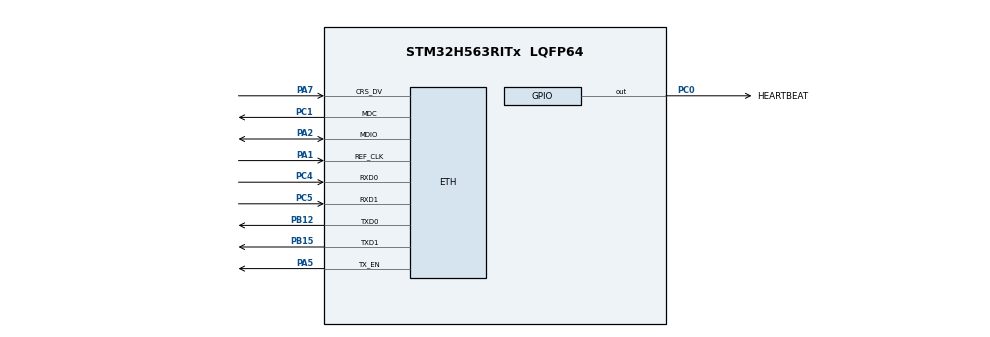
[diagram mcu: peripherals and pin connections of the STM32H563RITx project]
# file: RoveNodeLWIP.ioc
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CORTEX_M33_NS.Number-Cortex_Memory_Protection_Unit_Region0_OTP_RO_AREAS_Settings=MPU_REGION_NUMBER0
CORTEX_M33_NS.default_mode_Activation=1
CORTEX_M33_NS.userName=CORTEX_M33
ETH.MediaInterface=HAL_ETH_RMII_MODE
Mcu.Family=STM32H5
Mcu.Name=STM32H563RITx
Mcu.Package=LQFP64
NVIC.PriorityGroup=NVIC_PRIORITYGROUP_4
PA1.Mode=RMII
PA1.Signal=ETH_REF_CLK
PA2.Mode=RMII
PA2.Signal=ETH_MDIO
PA5.Mode=RMII
PA5.Signal=ETH_TX_EN
PA7.Mode=RMII
PA7.Signal=ETH_CRS_DV
PB12.Mode=RMII
PB12.Signal=ETH_TXD0
PB15.Mode=RMII
PB15.Signal=ETH_TXD1
PC0.GPIO_Label=HEARTBEAT
PC0.Signal=GPIO_Output
PC1.Mode=RMII
PC1.Signal=ETH_MDC
PC4.Mode=RMII
PC4.Signal=ETH_RXD0
PC5.Mode=RMII
PC5.Signal=ETH_RXD1
ProjectManager.HeapSize=0x200
ProjectManager.StackSize=0x400
ProjectManager.TargetToolchain=STM32CubeIDE
RCC.ADCFreq_Value=32000000
RCC.AHBFreq_Value=32000000
RCC.APB1Freq_Value=32000000
RCC.APB1TimFreq_Value=32000000
RCC.APB2Freq_Value=32000000
RCC.APB2TimFreq_Value=32000000
RCC.APB3Freq_Value=32000000
RCC.CSI_VALUE=4000000
RCC.CortexFreq_Value=32000000
RCC.EPOD_VALUE=4000000
RCC.HCLKFreq_Value=32000000
RCC.HSE_VALUE=25000000
RCC.HSI48_VALUE=48000000
RCC.HSI_VALUE=64000000
RCC.LSE_VALUE=32768
RCC.LSIRC_VALUE=32000
RCC.PLLFRACN=0
RCC.PLLN=32
RCC.SYSCLKFreq_VALUE=32000000
RCC.USBFreq_Value=48000000
RCC.VCOOutputFreq_Value=128000000
VP_BOOTPATH_VS_BOOTPATH.Mode=BP_Activate
VP_CORTEX_M33_NS_VS_Hclk.Mode=Hclk_Mode
VP_ICACHE_VS_ICACHE.Mode=DirectMappedCache
VP_MEMORYMAP_VS_MEMORYMAP.Mode=CurAppReg
VP_PWR_VS_LPOM.Mode=PowerOptimisation
VP_PWR_VS_SECSignals.Mode=Security/Privilege
board=custom

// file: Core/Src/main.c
/* USER CODE BEGIN Header */

/*

This is used to test the RoveNode's PHY. This has LwIP so when we get to it, nothing else changes.

*/

/**
  ******************************************************************************
  * @file           : main.c
  * @brief          : Main program body
  ******************************************************************************
  * @attention
  *
  * Copyright (c) 2026 STMicroelectronics.
  * All rights reserved.
  *
  * This software is licensed under terms that can be found in the LICENSE file
  * in the root directory of this software component.
  * If no LICENSE file comes with this software, it is provided AS-IS.
  *
  ******************************************************************************
  */
/* USER CODE END Header */
#include "main.h"
#include "string.h"

/* USER CODE BEGIN Includes */
#include "lwip.h"
#include "ethernetif.h"
#include "lwip/opt.h"
#include "lwip/init.h"
#include "netif/etharp.h"
#include "lwip/netif.h"
#include "lwip/timeouts.h"
#if LWIP_DHCP
#include "lwip/dhcp.h"
#endif

#include "cachel1_armv7.h"
/* USER CODE END Includes */

/* USER CODE BEGIN PD */

#define LAN8742A_PHY_ADDRESS 0

/* USER CODE END PD */

ETH_TxPacketConfigTypeDef TxConfig;
ETH_DMADescTypeDef  DMARxDscrTab[ETH_RX_DESC_CNT]; /* Ethernet Rx DMA Descriptors */
ETH_DMADescTypeDef  DMATxDscrTab[ETH_TX_DESC_CNT]; /* Ethernet Tx DMA Descriptors */

ETH_HandleTypeDef heth;

/* USER CODE BEGIN PV */
extern struct netif gnetif;
/* USER CODE END PV */

void SystemClock_Config(void);
static void MPU_Config(void);
static void MX_GPIO_Init(void);
static void MX_ICACHE_Init(void);
/* USER CODE BEGIN PFP */
static void Netif_Config(void);
void Test_ETH_Transmit(void);
/* USER CODE END PFP */

int main(void)
{

  /* USER CODE BEGIN 1 */
	SCB_DisableDCache();

  /* USER CODE END 1 */

  /* MCU Configuration--------------------------------------------------------*/

  /* MPU Configuration--------------------------------------------------------*/
  MPU_Config();

  /* Reset of all peripherals, Initializes the Flash interface and the Systick. */
  HAL_Init();

  /* Configure the system clock */
  SystemClock_Config();

  /* Initialize all configured peripherals */
  MX_GPIO_Init();
  MX_ICACHE_Init();
  /* USER CODE BEGIN 2 */
//  lwip_init();
//  Netif_Config();
//  udp_led_server_init();
  MX_ETH_Init();
  if (HAL_ETH_Start(&heth) == HAL_OK) // REMOVE FOR LWIP
	{

	} else {
	  while(1){
		  HAL_GPIO_TogglePin(HEARTBEAT_GPIO_Port, HEARTBEAT_Pin);
		  HAL_Delay(5000);
	  }
	}

//  uint32_t phy_reg = 0;
//  /* Read Register 0 (Basic Control Register) */
//  HAL_ETH_ReadPHYRegister(&heth, LAN8742A_PHY_ADDRESS, 0, &phy_reg);
//
//  /* Set Bit 14 (Loopback Mode) */
//  phy_reg |= (1U << 14);
//
//  /* Write back to Register 0 */
//  HAL_ETH_WritePHYRegister(&heth, LAN8742A_PHY_ADDRESS, 0, phy_reg);

  /* Disable Auto Negotiation
    NOTE: required for the PHY to output signals on RJ45
  */
  uint32_t reg0 = 0;
  HAL_ETH_ReadPHYRegister(&heth, 0, 0, &reg0);
  reg0 &= ~(1U << 12); // Disable Auto-Negotiation (Bit 12)
  reg0 |=  (1U << 13); // Force 100 Mbps (Bit 13)
  reg0 |=  (1U << 8);  // Force Full Duplex (Bit 8)
  HAL_ETH_WritePHYRegister(&heth, 0, 0, reg0);

  HAL_Delay(10);

  uint32_t what_reg = 0;
  HAL_ETH_ReadPHYRegister(&heth, 0, 0, &what_reg);

  uint32_t what_mode = 0;
  HAL_ETH_ReadPHYRegister(&heth, 0, 17, &what_mode);

  /* USER CODE END 2 */

  /* Infinite loop */
  /* USER CODE BEGIN WHILE */
  while (1) {
  /* Read a received packet from the Ethernet buffers and send it
  to the lwIP for handling */
  Test_ETH_Transmit();
  HAL_GPIO_TogglePin(HEARTBEAT_GPIO_Port, HEARTBEAT_Pin);
  HAL_Delay(1000);

//  ethernetif_input(&gnetif);
//  /* Handle timeouts */
//  sys_check_timeouts();
// #if LWIP_NETIF_LINK_CALLBACK
//  Ethernet_Link_Periodic_Handle(&gnetif);
// #endif
// #if LWIP_DHCP
//  DHCP_Periodic_Handle(&gnetif);
// #endif
    /* USER CODE END WHILE */

  }
}

void SystemClock_Config(void)
{
  RCC_OscInitTypeDef RCC_OscInitStruct = {0};
  RCC_ClkInitTypeDef RCC_ClkInitStruct = {0};

  /** Configure the main internal regulator output voltage
  */
  __HAL_PWR_VOLTAGESCALING_CONFIG(PWR_REGULATOR_VOLTAGE_SCALE0);

  while(!__HAL_PWR_GET_FLAG(PWR_FLAG_VOSRDY)) {}

  /** Initializes the RCC Oscillators according to the specified parameters
  * in the RCC_OscInitTypeDef structure.
  */
  RCC_OscInitStruct.OscillatorType = RCC_OSCILLATORTYPE_CSI;
  RCC_OscInitStruct.CSIState = RCC_CSI_ON;
  RCC_OscInitStruct.CSICalibrationValue = RCC_CSICALIBRATION_DEFAULT;
  RCC_OscInitStruct.PLL.PLLState = RCC_PLL_ON;
  RCC_OscInitStruct.PLL.PLLSource = RCC_PLL1_SOURCE_CSI;
  RCC_OscInitStruct.PLL.PLLM = 1;
  RCC_OscInitStruct.PLL.PLLN = 125;
  RCC_OscInitStruct.PLL.PLLP = 2;
  RCC_OscInitStruct.PLL.PLLQ = 2;
  RCC_OscInitStruct.PLL.PLLR = 2;
  RCC_OscInitStruct.PLL.PLLRGE = RCC_PLL1_VCIRANGE_2;
  RCC_OscInitStruct.PLL.PLLVCOSEL = RCC_PLL1_VCORANGE_WIDE;
  RCC_OscInitStruct.PLL.PLLFRACN = 0;
  if (HAL_RCC_OscConfig(&RCC_OscInitStruct) != HAL_OK)
  {
    Error_Handler();
  }

  /** Initializes the CPU, AHB and APB buses clocks
  */
  RCC_ClkInitStruct.ClockType = RCC_CLOCKTYPE_HCLK|RCC_CLOCKTYPE_SYSCLK
                              |RCC_CLOCKTYPE_PCLK1|RCC_CLOCKTYPE_PCLK2
                              |RCC_CLOCKTYPE_PCLK3;
  RCC_ClkInitStruct.SYSCLKSource = RCC_SYSCLKSOURCE_PLLCLK;
  RCC_ClkInitStruct.AHBCLKDivider = RCC_SYSCLK_DIV1;
  RCC_ClkInitStruct.APB1CLKDivider = RCC_HCLK_DIV1;
  RCC_ClkInitStruct.APB2CLKDivider = RCC_HCLK_DIV1;
  RCC_ClkInitStruct.APB3CLKDivider = RCC_HCLK_DIV1;

  if (HAL_RCC_ClockConfig(&RCC_ClkInitStruct, FLASH_LATENCY_5) != HAL_OK)
  {
    Error_Handler();
  }

  /** Configure the programming delay
  */
  __HAL_FLASH_SET_PROGRAM_DELAY(FLASH_PROGRAMMING_DELAY_2);
}

void MX_ETH_Init(void)
{

   static uint8_t MACAddr[6];

  heth.Instance = ETH;
  MACAddr[0] = 0x00;
  MACAddr[1] = 0x80;
  MACAddr[2] = 0xE1;
  MACAddr[3] = 0x00;
  MACAddr[4] = 0x00;
  MACAddr[5] = 0x00;
  heth.Init.MACAddr = &MACAddr[0];
  heth.Init.MediaInterface = HAL_ETH_RMII_MODE;
  heth.Init.TxDesc = DMATxDscrTab;
  heth.Init.RxDesc = DMARxDscrTab;
  heth.Init.RxBuffLen = 1524;

  if (HAL_ETH_Init(&heth) != HAL_OK)
  {
    Error_Handler();
  }

  memset(&TxConfig, 0 , sizeof(ETH_TxPacketConfigTypeDef));
  TxConfig.Attributes = ETH_TX_PACKETS_FEATURES_CSUM | ETH_TX_PACKETS_FEATURES_CRCPAD;
  TxConfig.ChecksumCtrl = ETH_CHECKSUM_IPHDR_PAYLOAD_INSERT_PHDR_CALC;
  TxConfig.CRCPadCtrl = ETH_CRC_PAD_INSERT;

}

static void MX_ICACHE_Init(void)
{

  /** Enable instruction cache in 1-way (direct mapped cache)
  */
  if (HAL_ICACHE_ConfigAssociativityMode(ICACHE_1WAY) != HAL_OK)
  {
    Error_Handler();
  }
  if (HAL_ICACHE_Enable() != HAL_OK)
  {
    Error_Handler();
  }

}

static void MX_GPIO_Init(void)
{
  GPIO_InitTypeDef GPIO_InitStruct = {0};

  /* GPIO Ports Clock Enable */
  __HAL_RCC_GPIOC_CLK_ENABLE();
  __HAL_RCC_GPIOA_CLK_ENABLE();
  __HAL_RCC_GPIOB_CLK_ENABLE();

  /*Configure GPIO pin Output Level */
  HAL_GPIO_WritePin(HEARTBEAT_GPIO_Port, HEARTBEAT_Pin, GPIO_PIN_RESET);

  /*Configure GPIO pin : HEARTBEAT_Pin */
  GPIO_InitStruct.Pin = HEARTBEAT_Pin;
  GPIO_InitStruct.Mode = GPIO_MODE_OUTPUT_PP;
  GPIO_InitStruct.Pull = GPIO_NOPULL;
  GPIO_InitStruct.Speed = GPIO_SPEED_FREQ_LOW;
  HAL_GPIO_Init(HEARTBEAT_GPIO_Port, &GPIO_InitStruct);

}

/* USER CODE BEGIN 4 */
/**
 * @brief Setup the network interface
 * None
 * @retval None
 */
static void Netif_Config(void) {
 ip_addr_t ipaddr;
 ip_addr_t netmask;
 ip_addr_t gw;
#if LWIP_DHCP
 ip_addr_set_zero_ip4(&ipaddr);
 ip_addr_set_zero_ip4(&netmask);
 ip_addr_set_zero_ip4(&gw);
#else
 /* IP address default setting */
 IP4_ADDR(&ipaddr, IP_ADDR0, IP_ADDR1, IP_ADDR2, IP_ADDR3);
 IP4_ADDR(&netmask, NETMASK_ADDR0, NETMASK_ADDR1 , NETMASK_ADDR2, NETMASK_ADDR3);
 IP4_ADDR(&gw, GW_ADDR0, GW_ADDR1, GW_ADDR2, GW_ADDR3);
#endif
 /* add the network interface */
 netif_add(&gnetif, &ipaddr, &netmask, &gw, NULL, &ethernetif_init,
 &ethernet_input);
 /* Registers the default network interface */
 netif_set_default(&gnetif);
#if LWIP_NETIF_LINK_CALLBACK
 netif_set_link_callback(&gnetif, ethernet_link_status_updated);
#if LWIP_DHCP
 dhcp_start(&gnetif);
 ethernet_link_status_updated(&gnetif);
#endif
#endif
}
/* USER CODE END 4 */

 /* MPU Configuration */

void MPU_Config(void)
{
  MPU_Region_InitTypeDef MPU_InitStruct = {0};
  MPU_Attributes_InitTypeDef MPU_AttributesInit = {0};

  /* Disables the MPU */
  HAL_MPU_Disable();

  /** Initializes and configures the Region 0 and the memory to be protected
  */
  MPU_InitStruct.Enable = MPU_REGION_ENABLE;
  MPU_InitStruct.Number = MPU_REGION_NUMBER0;
  MPU_InitStruct.BaseAddress = 0x08FFF000;
  MPU_InitStruct.LimitAddress = 0x08FFFFFF;
  MPU_InitStruct.AttributesIndex = MPU_ATTRIBUTES_NUMBER0;
  MPU_InitStruct.AccessPermission = MPU_REGION_ALL_RO;
  MPU_InitStruct.DisableExec = MPU_INSTRUCTION_ACCESS_DISABLE;
  MPU_InitStruct.IsShareable = MPU_ACCESS_NOT_SHAREABLE;

  HAL_MPU_ConfigRegion(&MPU_InitStruct);

  /** Initializes and configures the Attribute 0 and the memory to be protected
  */
  MPU_AttributesInit.Number = MPU_ATTRIBUTES_NUMBER0;
  MPU_AttributesInit.Attributes = INNER_OUTER(MPU_NOT_CACHEABLE);

  HAL_MPU_ConfigMemoryAttributes(&MPU_AttributesInit);
  /* Enables the MPU */
  HAL_MPU_Enable(MPU_PRIVILEGED_DEFAULT);

}

/* Standard 64-byte raw Ethernet test frame */
void Test_ETH_Transmit(void)
{
  /* Aligned buffer for DMA safety */
  __attribute__((aligned(32))) static uint8_t tx_buffer[64];

  /* 1. Destination MAC: Broadcast (FF:FF:FF:FF:FF:FF) */
  memset(&tx_buffer[0], 0xFF, 6);

  /* 2. Source MAC: STM32 MAC Address (00:80:E1:00:00:00) */
  tx_buffer[6]  = 0x00;
  tx_buffer[7]  = 0x80;
  tx_buffer[8]  = 0xE1;
  tx_buffer[9]  = 0x00;
  tx_buffer[10] = 0x00;
  tx_buffer[11] = 0x00;

  /* 3. EtherType: Custom / Test (0x88B5 - IEEE Std 802.1 Local Experimental) */
  tx_buffer[12] = 0x88;
  tx_buffer[13] = 0xB5;

  /* 4. Payload: Pattern fill */
  for (int i = 14; i < 64; i++) {
    tx_buffer[i] = (uint8_t)(i - 14);
  }

  /* 5. Set up HAL Tx Packet Configuration Structure */
  ETH_TxPacketConfig TxConfig = {0};
  TxConfig.Attributes   = ETH_TX_PACKETS_FEATURES_CRCPAD; // MCU generates CRC
  TxConfig.ChecksumCtrl = ETH_CHECKSUM_DISABLE;          // Disable IP checksum offload for raw frame
  TxConfig.CRCPadCtrl   = ETH_CRC_PAD_INSERT;
  TxConfig.Length       = 64;

  struct __ETH_BufferTypeDef eth_buff = {
		  .buffer = tx_buffer,
		  .len = 64,
		  .next = NULL,
  };

  TxConfig.TxBuffer     = &eth_buff;

  /* 6. Transmit Frame */
  HAL_StatusTypeDef status = HAL_ETH_Transmit(&heth, &TxConfig, 1000);

  if (status == HAL_OK) {
    /* Success: Frame pushed to DMA buffer */
  } else {
    /* Error: HAL_TIMEOUT, HAL_BUSY, or HAL_ERROR */
	  while(1)
	  {
		  HAL_GPIO_TogglePin(HEARTBEAT_GPIO_Port, HEARTBEAT_Pin);
		  HAL_Delay(100);
		  HAL_GPIO_TogglePin(HEARTBEAT_GPIO_Port, HEARTBEAT_Pin);
		  HAL_Delay(100);
		  HAL_GPIO_TogglePin(HEARTBEAT_GPIO_Port, HEARTBEAT_Pin);
		  HAL_Delay(100);
		  HAL_GPIO_TogglePin(HEARTBEAT_GPIO_Port, HEARTBEAT_Pin);
		  HAL_Delay(100);
	  }
  }
}

void Error_Handler(void)
{
  __disable_irq();
  while (1)
  {
  }
}
